One B-rep face of a CAD part: STEP entity #617.
In plain terms, the planar face has unit normal (-1, 0, 0).
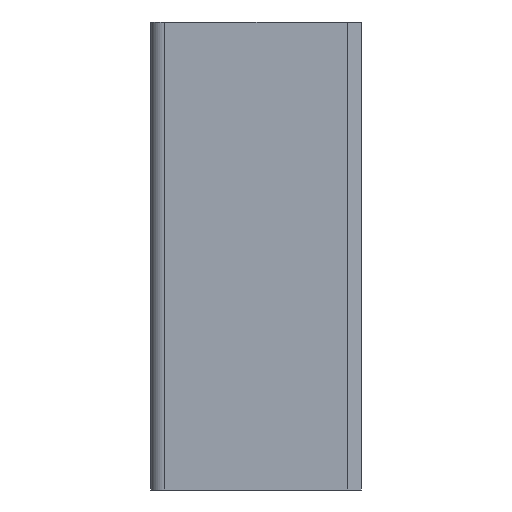
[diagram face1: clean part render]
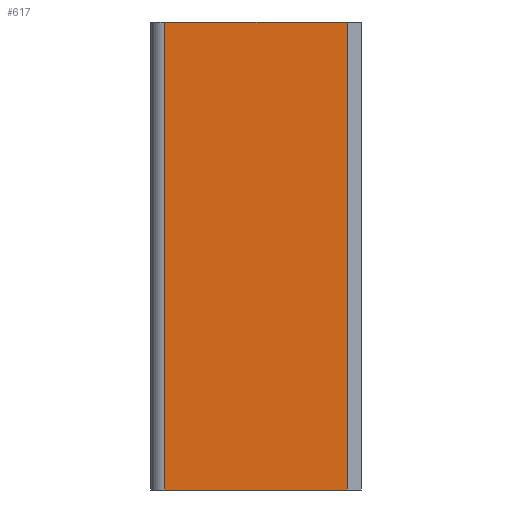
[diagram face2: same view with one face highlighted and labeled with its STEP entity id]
Its self-contained STEP definition (entity closure, numbers rounded to 3 decimals):
#97=CARTESIAN_POINT('Line Origine',(0.,22.5,0.)) ;
#101=CARTESIAN_POINT('Vertex',(0.,42.,0.)) ;
#103=CARTESIAN_POINT('Vertex',(0.,3.,0.)) ;
#520=CARTESIAN_POINT('Line Origine',(0.,22.5,-100.)) ;
#524=CARTESIAN_POINT('Vertex',(0.,42.,-100.)) ;
#526=CARTESIAN_POINT('Vertex',(0.,3.,-100.)) ;
#596=CARTESIAN_POINT('Axis2P3D Location',(0.,42.,-100.)) ;
#601=CARTESIAN_POINT('Line Origine',(0.,42.,-50.)) ;
#606=CARTESIAN_POINT('Line Origine',(0.,3.,-50.)) ;
#98=DIRECTION('Vector Direction',(0.,-1.,0.)) ;
#521=DIRECTION('Vector Direction',(0.,-1.,0.)) ;
#597=DIRECTION('Axis2P3D Direction',(-1.,0.,0.)) ;
#598=DIRECTION('Axis2P3D XDirection',(0.,0.,1.)) ;
#602=DIRECTION('Vector Direction',(0.,0.,1.)) ;
#607=DIRECTION('Vector Direction',(0.,0.,1.)) ;
#599=AXIS2_PLACEMENT_3D('Plane Axis2P3D',#596,#597,#598) ;
#612=ORIENTED_EDGE('',*,*,#105,.F.) ;
#613=ORIENTED_EDGE('',*,*,#605,.F.) ;
#614=ORIENTED_EDGE('',*,*,#528,.T.) ;
#615=ORIENTED_EDGE('',*,*,#610,.T.) ;
#99=VECTOR('Line Direction',#98,1.) ;
#522=VECTOR('Line Direction',#521,1.) ;
#603=VECTOR('Line Direction',#602,1.) ;
#608=VECTOR('Line Direction',#607,1.) ;
#617=ADVANCED_FACE('A935-10017045',(#616),#600,.T.) ;
#105=EDGE_CURVE('',#102,#104,#100,.T.) ;
#528=EDGE_CURVE('',#525,#527,#523,.T.) ;
#605=EDGE_CURVE('',#525,#102,#604,.T.) ;
#610=EDGE_CURVE('',#527,#104,#609,.T.) ;
#611=EDGE_LOOP('',(#612,#613,#614,#615)) ;
#616=FACE_OUTER_BOUND('',#611,.T.) ;
#100=LINE('Line',#97,#99) ;
#523=LINE('Line',#520,#522) ;
#604=LINE('Line',#601,#603) ;
#609=LINE('Line',#606,#608) ;
#600=PLANE('Plane',#599) ;
#102=VERTEX_POINT('',#101) ;
#104=VERTEX_POINT('',#103) ;
#525=VERTEX_POINT('',#524) ;
#527=VERTEX_POINT('',#526) ;
